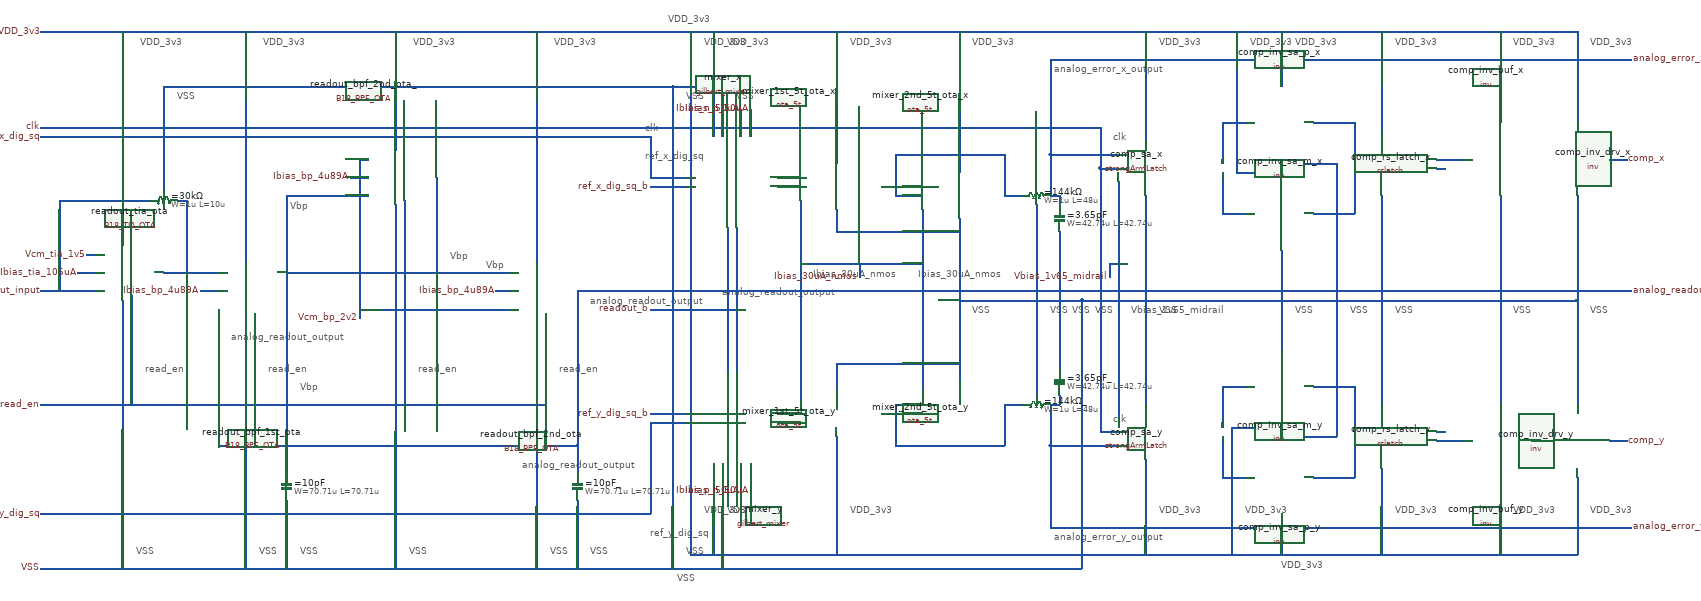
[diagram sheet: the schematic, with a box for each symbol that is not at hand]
v {xschem version=3.4.8RC file_version=1.3}
G {}
K {}
V {}
S {}
F {}
E {}
T {VDD_3v3} 1310 570 0 0 0.4 0.4 {}
T {VSS} 800 10 1 0 0.4 0.4 {}
T {VSS} -20 600 0 0 0.4 0.4 {}
T {Ibias_30uA_nmos} 280 -70 1 0 0.4 0.4 {}
T {Ibias_30uA_nmos} 510 -70 1 0 0.4 0.4 {}
T {VSS} 850 10 1 0 0.4 0.4 {}
T {VSS} 900 10 1 0 0.4 0.4 {}
T {Vbias_1v65_midrail} 980 10 1 0 0.4 0.4 {}
T {VSS} 630 10 1 0 0.4 0.4 {}
T {VSS} 1040 10 1 0 0.4 0.4 {}
T {VSS} 1340 10 1 0 0.4 0.4 {}
T {VSS} 1460 10 1 0 0.4 0.4 {}
T {VSS} 1560 10 1 0 0.4 0.4 {}
T {VSS} 1820 10 1 0 0.4 0.4 {}
T {VSS} 1990 10 1 0 0.4 0.4 {}
T {VDD_3v3} 360 450 1 0 0.4 0.4 {}
T {VDD_3v3} 1230 450 1 0 0.4 0.4 {}
T {VDD_3v3} 1560 450 1 0 0.4 0.4 {}
T {VDD_3v3} 1820 450 1 0 0.4 0.4 {}
T {VDD_3v3} 1990 450 1 0 0.4 0.4 {}
T {VDD_3v3} 1990 -580 1 0 0.4 0.4 {}
T {VDD_3v3} 1820 -580 1 0 0.4 0.4 {}
T {VDD_3v3} 1560 -580 1 0 0.4 0.4 {}
T {VDD_3v3} 1340 -580 1 0 0.4 0.4 {}
T {VDD_3v3} 1240 -580 1 0 0.4 0.4 {}
T {VDD_3v3} 630 -580 1 0 0.4 0.4 {}
T {VDD_3v3} 360 -580 1 0 0.4 0.4 {}
T {VDD_3v3} 90 -580 1 0 0.4 0.4 {}
T {VDD_3v3} 40 -580 1 0 0.4 0.4 {}
T {VDD_3v3} 40 450 1 0 0.4 0.4 {}
T {VDD_3v3} 90 450 1 0 0.4 0.4 {}
T {VDD_3v3} -40 -630 0 0 0.4 0.4 {}
T {VSS} 110 -460 1 0 0.4 0.4 {}
T {VSS} 0 540 1 0 0.4 0.4 {}
T {clk} 940 -370 1 0 0.4 0.4 {}
T {clk} 940 250 1 0 0.4 0.4 {}
T {VDD_3v3} 1040 450 1 0 0.4 0.4 {}
T {VDD_3v3} 1040 -580 1 0 0.4 0.4 {}
T {analog_error_y_output} 810 510 0 0 0.4 0.4 {}
T {analog_error_x_output} 810 -520 0 0 0.4 0.4 {}
T {VSS} -300 540 1 0 0.4 0.4 {}
T {VSS} -210 540 1 0 0.4 0.4 {}
T {VSS} -610 540 1 0 0.4 0.4 {}
T {VSS} -940 540 1 0 0.4 0.4 {}
T {VSS} -1210 540 1 0 0.4 0.4 {}
T {VSS} -1120 -460 1 0 0.4 0.4 {}
T {VSS} 0 -460 1 0 0.4 0.4 {}
T {VDD_3v3} -1200 -580 1 0 0.4 0.4 {}
T {VDD_3v3} -930 -580 1 0 0.4 0.4 {}
T {VDD_3v3} -600 -580 1 0 0.4 0.4 {}
T {VDD_3v3} -290 -580 1 0 0.4 0.4 {}
T {read_en} -920 140 1 0 0.4 0.4 {}
T {read_en} -280 140 1 0 0.4 0.4 {}
T {analog_readout_output} -210 -10 1 0 0.4 0.4 {}
T {Vbp} -870 -220 0 0 0.4 0.4 {}
T {Vbp} -440 -90 0 0 0.4 0.4 {}
T {Vbp} -850 180 1 0 0.4 0.4 {}
T {Vbp} -520 -110 1 0 0.4 0.4 {}
T {read_en} -590 140 1 0 0.4 0.4 {}
T {read_en} -1190 140 1 0 0.4 0.4 {}
T {analog_readout_output} -1000 70 1 0 0.4 0.4 {}
T {analog_readout_output} -360 350 2 0 0.4 0.4 {}
T {VSS} -850 540 1 0 0.4 0.4 {}
T {analog_readout_output} 80 -30 2 0 0.4 0.4 {}
T {ref_y_dig_sq} -80 500 2 0 0.4 0.4 {}
T {ref_x_dig_sq} -90 -330 2 0 0.4 0.4 {}
T {clk} -90 -390 2 0 0.4 0.4 {}
N 200 -250 250 -250 {lab=#net1}
N 200 -270 250 -270 {lab=#net2}
N 430 -250 520 -250 {lab=#net3}
N 460 -230 520 -230 {lab=#net4}
N 60 -590 60 -360 {lab=VDD_3v3}
N 330 -590 330 -300 {lab=VDD_3v3}
N 600 -590 600 -280 {lab=VDD_3v3}
N 460 -320 460 -230 {lab=#net4}
N 460 -320 700 -320 {lab=#net4}
N 700 -320 700 -230 {lab=#net4}
N 700 -230 740 -230 {lab=#net4}
N 250 -220 250 -130 {lab=Ibias_30uA_nmos}
N 520 -200 520 -130 {lab=Ibias_30uA_nmos}
N 330 -200 330 -150 {lab=VSS}
N 800 -320 800 -230 {lab=analog_error_x_output}
N 910 -290 950 -290 {lab=clk}
N 1180 -280 1180 -190 {lab=#net5}
N 1180 -190 1230 -190 {lab=#net5}
N 1180 -390 1180 -300 {lab=#net6}
N 1180 -390 1230 -390 {lab=#net6}
N 1310 -280 1310 -270 {lab=VDD_3v3}
N 1210 -280 1310 -280 {lab=VDD_3v3}
N 1310 -310 1310 -300 {lab=VSS}
N 1310 -300 1430 -300 {lab=VSS}
N 1380 -190 1470 -190 {lab=#net7}
N 1470 -290 1470 -190 {lab=#net7}
N 1380 -390 1470 -390 {lab=#net8}
N 1470 -390 1470 -310 {lab=#net8}
N 1530 -590 1530 -370 {lab=VDD_3v3}
N 1210 -590 1210 -280 {lab=VDD_3v3}
N 1310 -590 1310 -470 {lab=VDD_3v3}
N 1650 -290 1670 -290 {lab=#net9}
N 1650 -310 1710 -310 {lab=#net10}
N 1790 -590 1790 -390 {lab=VDD_3v3}
N 1960 -590 1960 -390 {lab=VDD_3v3}
N 2030 -310 2070 -310 {lab=comp_x}
N 330 -150 600 -150 {lab=VSS}
N 800 -320 950 -320 {lab=analog_error_x_output}
N 910 -380 910 -290 {lab=clk}
N 120 -420 120 -360 {lab=Ibias_n_50uA}
N 140 -420 140 -360 {lab=Ibias_p_50uA}
N 800 -230 820 -230 {lab=analog_error_x_output}
N 820 -230 820 -210 {lab=analog_error_x_output}
N 1530 -230 1530 230 {lab=VSS}
N 1790 -230 1790 230 {lab=VSS}
N 1960 -230 1960 230 {lab=VSS}
N 1310 -110 1310 110 {lab=VSS}
N 1310 300 1310 310 {lab=VSS}
N 1310 270 1310 280 {lab=VDD_3v3}
N 1200 280 1310 280 {lab=VDD_3v3}
N 1180 190 1180 280 {lab=#net11}
N 1180 190 1230 190 {lab=#net11}
N 1180 300 1180 390 {lab=#net12}
N 1180 390 1230 390 {lab=#net12}
N 1380 190 1470 190 {lab=#net13}
N 1470 190 1470 290 {lab=#net13}
N 1380 390 1470 390 {lab=#net14}
N 1470 310 1470 390 {lab=#net14}
N 1650 290 1670 290 {lab=#net15}
N 1650 310 1710 310 {lab=#net16}
N 1860 310 1880 310 {lab=#net17}
N 2030 310 2070 310 {lab=comp_y}
N 1010 -230 1010 230 {lab=VSS}
N 820 -150 820 150 {lab=VSS}
N 770 -210 770 210 {lab=VSS}
N 600 -180 600 180 {lab=VSS}
N 430 250 520 250 {lab=#net18}
N 460 230 520 230 {lab=#net19}
N 460 230 460 320 {lab=#net19}
N 460 320 700 320 {lab=#net19}
N 700 230 700 320 {lab=#net19}
N 700 230 740 230 {lab=#net19}
N 800 230 800 320 {lab=analog_error_y_output}
N 800 320 950 320 {lab=analog_error_y_output}
N 800 230 820 230 {lab=analog_error_y_output}
N 820 210 820 230 {lab=analog_error_y_output}
N 330 140 330 200 {lab=VSS}
N 330 140 600 140 {lab=VSS}
N 250 -130 250 220 {lab=Ibias_30uA_nmos}
N 520 -130 520 200 {lab=Ibias_30uA_nmos}
N 910 -290 910 290 {lab=clk}
N 910 290 950 290 {lab=clk}
N 950 -260 950 260 {lab=Vbias_1v65_midrail}
N 380 -80 380 -50 {lab=Ibias_30uA_nmos}
N 930 -80 930 -50 {lab=Vbias_1v65_midrail}
N 930 -80 950 -80 {lab=Vbias_1v65_midrail}
N 250 -80 520 -80 {lab=Ibias_30uA_nmos}
N 90 -160 90 160 {lab=analog_readout_output}
N 110 -160 110 160 {lab=readout_b}
N 120 360 120 420 {lab=Ibias_p_50uA}
N 140 360 140 420 {lab=Ibias_n_50uA}
N 200 250 250 250 {lab=#net20}
N 200 270 250 270 {lab=#net21}
N 600 0 770 0 {lab=VSS}
N 770 0 820 0 {lab=VSS}
N 820 -0 870 0 {lab=VSS}
N 870 0 870 590 {lab=VSS}
N 870 0 1010 0 {lab=VSS}
N 1790 0 1960 0 {lab=VSS}
N 1530 0 1790 -0 {lab=VSS}
N 1310 0 1530 0 {lab=VSS}
N 1010 0 1310 -0 {lab=VSS}
N 330 300 330 560 {lab=VDD_3v3}
N 10 560 330 560 {lab=VDD_3v3}
N 10 -590 10 560 {lab=VDD_3v3}
N 1430 -300 1430 0 {lab=VSS}
N 1310 300 1430 300 {lab=VSS}
N 1430 0 1430 300 {lab=VSS}
N 60 360 60 560 {lab=VDD_3v3}
N 1200 280 1200 560 {lab=VDD_3v3}
N 330 560 1200 560 {lab=VDD_3v3}
N 1200 560 1960 560 {lab=VDD_3v3}
N 1960 390 1960 560 {lab=VDD_3v3}
N 1790 390 1790 560 {lab=VDD_3v3}
N 1530 370 1530 560 {lab=VDD_3v3}
N 1310 470 1310 560 {lab=VDD_3v3}
N 80 -470 80 -360 {lab=VSS}
N -30 -470 80 -470 {lab=VSS}
N -30 -470 -30 590 {lab=VSS}
N -80 250 -0 250 {lab=ref_y_dig_sq_b}
N -80 270 -0 270 {lab=#net22}
N -80 20 110 20 {lab=readout_b}
N -80 -20 90 -20 {lab=analog_readout_output}
N -80 -250 -0 -250 {lab=ref_x_dig_sq_b}
N -80 -270 -0 -270 {lab=ref_x_dig_sq}
N 1010 350 1010 560 {lab=VDD_3v3}
N 1010 -590 1010 -350 {lab=VDD_3v3}
N 800 320 800 500 {lab=analog_error_y_output}
N 800 500 2080 500 {lab=analog_error_y_output}
N 800 -530 800 -320 {lab=analog_error_x_output}
N 800 -530 2080 -530 {lab=analog_error_x_output}
N 80 360 80 590 {lab=VSS}
N -240 -20 -80 -20 {lab=analog_readout_output}
N 90 -20 2080 -20 {lab=analog_readout_output}
N -310 30 -310 230 {lab=read_en}
N -950 30 -950 230 {lab=read_en}
N -1150 -60 -1030 -60 {lab=#net23}
N -1100 -220 -1100 -60 {lab=#net23}
N -1120 -220 -1100 -220 {lab=#net23}
N -1150 -470 -1150 -240 {lab=VSS}
N -1150 -470 -30 -470 {lab=VSS}
N -330 -590 -330 -80 {lab=VDD_3v3}
N -970 -590 -970 -80 {lab=VDD_3v3}
N -1240 -590 -1240 -120 {lab=VDD_3v3}
N -1220 -10 -1220 230 {lab=read_en}
N -1340 -60 -1300 -60 {lab=Ibias_tia_105uA}
N -1420 -20 -1300 -20 {lab=analog_readout_input}
N -1420 -590 1960 -590 {lab=VDD_3v3}
N -1240 -0 -1240 590 {lab=VSS}
N -970 40 -970 590 {lab=VSS}
N -330 40 -330 590 {lab=VSS}
N -1420 590 870 590 {lab=VSS}
N -550 -270 -550 -120 {lab=#net24}
N -550 -120 -550 -60 {lab=#net24}
N -740 -270 -700 -270 {lab=Ibias_bp_4u89A}
N -420 -20 -390 -20 {lab=Ibias_bp_4u89A}
N -1070 -20 -1030 -20 {lab=Ibias_bp_4u89A}
N -720 -310 -700 -310 {lab=Vcm_bp_2v2}
N -720 20 -390 20 {lab=Vcm_bp_2v2}
N -720 -310 -720 40 {lab=Vcm_bp_2v2}
N -880 -230 -700 -230 {lab=#net24}
N -880 -60 -390 -60 {lab=#net24}
N -620 -220 -620 230 {lab=read_en}
N -1030 320 -240 320 {lab=analog_readout_output}
N -240 -20 -240 320 {lab=analog_readout_output}
N -1030 20 -1030 320 {lab=analog_readout_output}
N -240 320 -240 380 {lab=analog_readout_output}
N -240 440 -240 590 {lab=VSS}
N -640 -210 -640 590 {lab=VSS}
N -640 -590 -640 -330 {lab=VDD_3v3}
N -880 -230 -880 380 {lab=#net24}
N -880 440 -880 590 {lab=VSS}
N -80 270 -80 470 {lab=#net22}
N -1420 -380 910 -380 {lab=clk}
N -80 -360 -80 -270 {lab=ref_x_dig_sq}
N -1420 -360 -80 -360 {lab=ref_x_dig_sq}
N -1380 -220 -1180 -220 {lab=analog_readout_input}
N -1380 -220 -1380 -20 {lab=analog_readout_input}
N -1320 -100 -1300 -100 {lab=Vcm_tia_1v5}
N -1420 230 -310 230 {lab=read_en}
N -1420 470 -80 470 {lab=#net22}
C {Analog/schematics/2_mixer/gilbert_mixer.sym} 100 -260 0 0 {name=mixer_x}
C {Analog/schematics/2_mixer/ota_5t.sym} 270 -200 0 0 {name=mixer_1st_5t_ota_x}
C {Analog/schematics/2_mixer/ota_5t.sym} 540 -180 0 0 {name=mixer_2nd_5t_ota_x}
C {Analog/schematics/3_comparator/strongArmLatch.sym} 1090 -300 0 0 {name=comp_sa_x}
C {Analog/schematics/3_comparator/inv.sym} 1230 -470 0 0 {name=comp_inv_sa_p_x}
C {Analog/schematics/3_comparator/inv.sym} 1230 -270 0 0 {name=comp_inv_sa_m_x}
C {Analog/schematics/3_comparator/rslatch.sym} 1570 -290 0 0 {name=comp_rs_latch_x}
C {Analog/schematics/3_comparator/inv.sym} 1710 -390 0 0 {name=comp_inv_buf_x}
C {Analog/schematics/3_comparator/inv.sym} 1880 -390 0 0 {name=comp_inv_drv_x}
C {lab_pin.sym} 120 -420 1 0 {name=p3 sig_type=std_logic lab=Ibias_n_50uA}
C {lab_pin.sym} 140 -420 1 0 {name=p4 sig_type=std_logic lab=Ibias_p_50uA}
C {lab_pin.sym} -1420 -360 2 1 {name=p5 sig_type=std_logic lab=ref_x_dig_sq}
C {lab_pin.sym} -80 -250 2 1 {name=p6 sig_type=std_logic lab=ref_x_dig_sq_b}
C {lab_pin.sym} 380 -50 1 1 {name=p7 sig_type=std_logic lab=Ibias_30uA_nmos}
C {symbols/ppolyf_u_3k.sym} 770 -230 3 0 {name="=144kΩ"
W=1u
L=48u
model=ppolyf_u_3k
spiceprefix=r
m=1
}
C {symbols/cap_mim_analog.sym} 820 -180 0 0 {name="=3.65pF"
W=42.74u
L=42.74u
model="cap_mim_2f0
_m3m4_noshield"
spiceprefix=c
m=1}
C {noconn.sym} 1670 -290 2 0 {name=l15}
C {lab_pin.sym} 2070 -310 2 0 {name=p8 sig_type=std_logic lab=comp_x}
C {lab_pin.sym} -1420 590 2 1 {name=p2 sig_type=std_logic lab=VSS}
C {lab_pin.sym} -1420 -380 2 1 {name=p9 sig_type=std_logic lab=clk}
C {lab_pin.sym} -80 20 2 1 {name=p11 sig_type=std_logic lab=readout_b}
C {Analog/schematics/2_mixer/gilbert_mixer.sym} 100 260 2 1 {name=mixer_y}
C {Analog/schematics/2_mixer/ota_5t.sym} 270 200 2 1 {name=mixer_1st_5t_ota_y}
C {Analog/schematics/2_mixer/ota_5t.sym} 540 180 2 1 {name=mixer_2nd_5t_ota_y}
C {Analog/schematics/3_comparator/strongArmLatch.sym} 1090 300 2 1 {name=comp_sa_y}
C {Analog/schematics/3_comparator/inv.sym} 1230 470 2 1 {name=comp_inv_sa_p_y}
C {Analog/schematics/3_comparator/inv.sym} 1230 270 2 1 {name=comp_inv_sa_m_y}
C {Analog/schematics/3_comparator/rslatch.sym} 1570 290 2 1 {name=comp_rs_latch_y}
C {Analog/schematics/3_comparator/inv.sym} 1710 390 2 1 {name=comp_inv_buf_y}
C {Analog/schematics/3_comparator/inv.sym} 1880 390 2 1 {name=comp_inv_drv_y}
C {symbols/ppolyf_u_3k.sym} 770 230 3 1 {name="=144kΩ_"
W=1u
L=48u
model=ppolyf_u_3k
spiceprefix=r
m=1
}
C {symbols/cap_mim_analog.sym} 820 180 2 1 {name="=3.65pF_"
W=42.74u
L=42.74u
model="cap_mim_2f0
_m3m4_noshield"
spiceprefix=c
m=1}
C {noconn.sym} 1670 290 2 0 {name=l1}
C {lab_pin.sym} 2070 310 2 0 {name=p12 sig_type=std_logic lab=comp_y}
C {lab_pin.sym} 930 -50 1 1 {name=p13 sig_type=std_logic lab=Vbias_1v65_midrail}
C {lab_pin.sym} -80 250 2 1 {name=p15 sig_type=std_logic lab=ref_y_dig_sq_b}
C {lab_pin.sym} 140 420 1 1 {name=p16 sig_type=std_logic lab=Ibias_n_50uA}
C {lab_pin.sym} 120 420 1 1 {name=p17 sig_type=std_logic lab=Ibias_p_50uA}
C {lab_pin.sym} 2080 500 2 0 {name=p18 sig_type=std_logic lab=analog_error_y_output}
C {lab_pin.sym} 2080 -530 2 0 {name=p19 sig_type=std_logic lab=analog_error_x_output}
C {Analog/schematics/1_readout/tia/B18_TIA_OTA.sym} -1290 0 0 0 {name=readout_tia_ota}
C {Analog/schematics/1_readout/bpf/B18_BPF_OTA.sym} -1030 40 0 0 {name=readout_bpf_1st_ota}
C {Analog/schematics/1_readout/bpf/B18_BPF_OTA.sym} -390 40 0 0 {name=readout_bpf_2nd_ota}
C {symbols/cap_mim_2f0fF.sym} -880 410 0 0 {name="=10pF"
W=70.71u
L=70.71u
model=cap_mim_2f0fF
spiceprefix=c
m=1}
C {symbols/cap_mim_2f0fF.sym} -240 410 0 0 {name="=10pF_"
W=70.71u
L=70.71u
model=cap_mim_2f0fF
spiceprefix=X
m=1}
C {symbols/ppolyf_u_3k.sym} -1150 -220 3 1 {name="=30kΩ"
W=1u
L=10u
model=ppolyf_u_3k
spiceprefix=X
m=1}
C {lab_pin.sym} 2080 -20 2 0 {name=p10 sig_type=std_logic lab=analog_readout_output}
C {lab_pin.sym} -420 -20 2 1 {name=p22 sig_type=std_logic lab=Ibias_bp_4u89A}
C {lab_pin.sym} -720 40 1 1 {name=p24 sig_type=std_logic lab=Vcm_bp_2v2}
C {lab_pin.sym} -1320 -100 1 0 {name=p20 sig_type=std_logic lab=Vcm_tia_1v5}
C {lab_pin.sym} -1340 -60 1 0 {name=p25 sig_type=std_logic lab=Ibias_tia_105uA}
C {lab_pin.sym} -1420 -20 2 1 {name=p26 sig_type=std_logic lab=analog_readout_input}
C {lab_pin.sym} -1420 -590 2 1 {name=p27 sig_type=std_logic lab=VDD_3v3}
C {Analog/schematics/1_readout/bpf/B18_BPF_OTA.sym} -700 -210 0 0 {name=readout_bpf_2nd_ota_}
C {lab_pin.sym} -740 -270 2 1 {name=p1 sig_type=std_logic lab=Ibias_bp_4u89A}
C {lab_pin.sym} -1070 -20 1 1 {name=p23 sig_type=std_logic lab=Ibias_bp_4u89A}
C {lab_pin.sym} -1420 230 2 1 {name=p14 sig_type=std_logic lab=read_en}
C {lab_pin.sym} -1420 470 2 1 {name=p21 sig_type=std_logic lab=ref_y_dig_sq}
